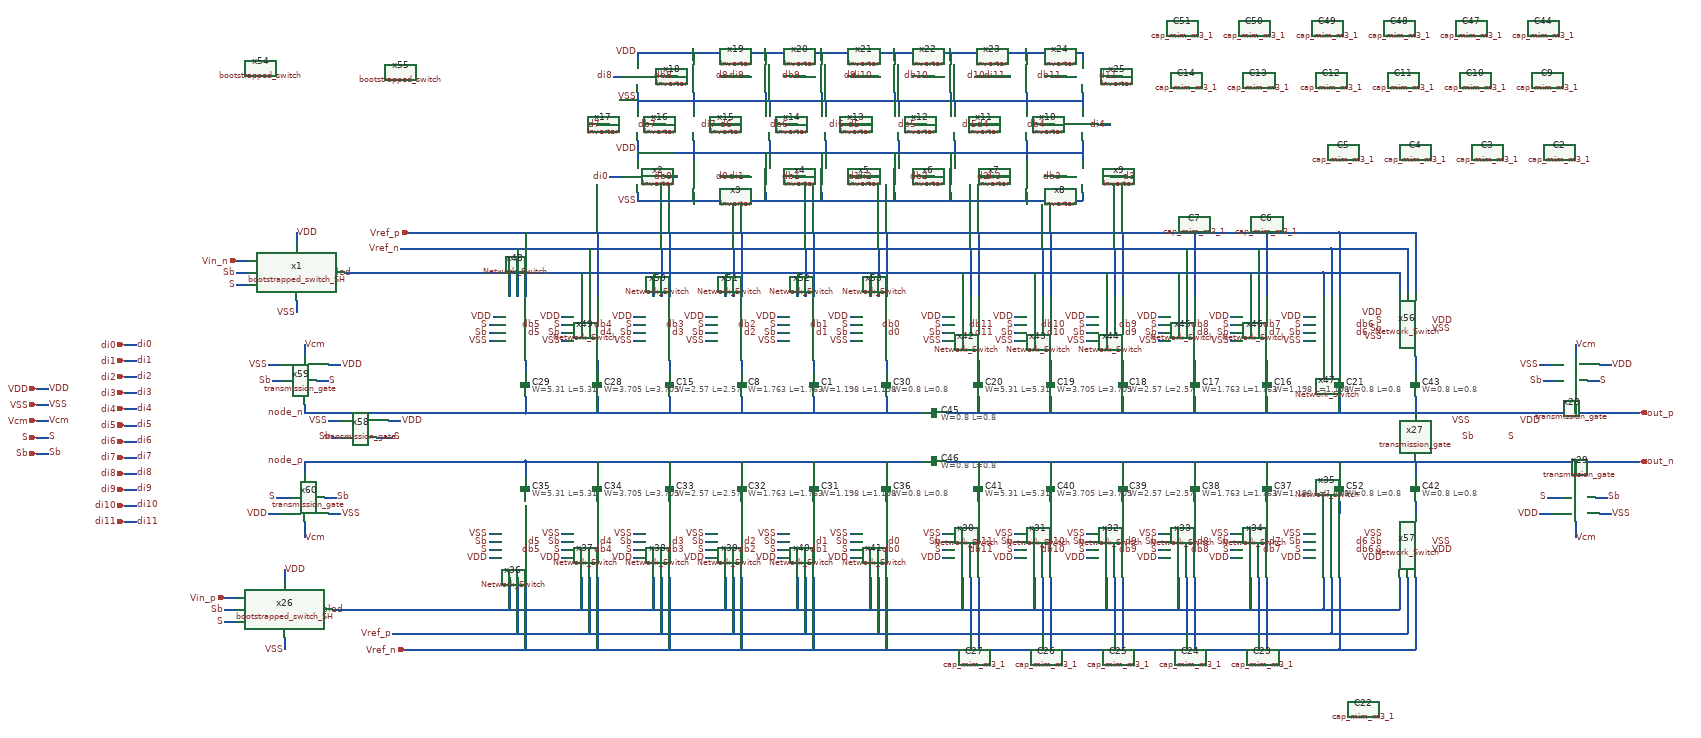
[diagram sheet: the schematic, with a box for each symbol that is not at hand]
v {xschem version=3.4.6 file_version=1.2}
G {}
K {}
V {}
S {}
E {}
N -790 70 -790 100 {lab=node_p}
N -530 70 190 70 {lab=node_p}
N 270 70 990 70 {lab=out_n}
N 1240 70 1240 100 {lab=out_n}
N 1060 70 1060 100 {lab=out_n}
N 880 70 880 100 {lab=out_n}
N 700 70 700 100 {lab=out_n}
N 520 70 520 100 {lab=out_n}
N 340 70 340 100 {lab=out_n}
N 110 70 110 100 {lab=node_p}
N -70 70 -70 100 {lab=node_p}
N -250 70 -250 100 {lab=node_p}
N -430 70 -430 100 {lab=node_p}
N -610 70 -610 100 {lab=node_p}
N -790 -80 -790 -50 {lab=node_n}
N -530 -50 190 -50 {lab=node_n}
N 270 -50 990 -50 {lab=out_p}
N 110 -80 110 -50 {lab=node_n}
N -70 -80 -70 -50 {lab=node_n}
N -250 -80 -250 -50 {lab=node_n}
N -430 -80 -430 -50 {lab=node_n}
N -610 -80 -610 -50 {lab=node_n}
N 1600 -50 1990 -50 {lab=out_p}
N 1600 70 1990 70 {lab=out_n}
N -660 70 -530 70 {lab=node_p}
N -790 70 -660 70 {lab=node_p}
N 990 70 1450 70 {lab=out_n}
N 110 180 110 200 {lab=#net1}
N -70 180 -70 200 {lab=#net2}
N -250 180 -250 200 {lab=#net3}
N -430 180 -430 200 {lab=#net4}
N -610 180 -610 200 {lab=#net5}
N -790 180 -790 200 {lab=#net6}
N 990 -50 1450 -50 {lab=out_p}
N 340 180 340 200 {lab=#net7}
N 520 180 520 200 {lab=#net8}
N 700 180 700 200 {lab=#net9}
N 880 180 880 200 {lab=#net10}
N 1240 180 1240 200 {lab=#net11}
N 1060 180 1060 200 {lab=#net12}
N -790 -50 -530 -50 {lab=node_n}
N 110 -180 110 -160 {lab=#net13}
N -70 -180 -70 -160 {lab=#net14}
N -250 -180 -250 -160 {lab=#net15}
N -430 -180 -430 -160 {lab=#net16}
N -610 -180 -610 -160 {lab=#net17}
N -790 -180 -790 -160 {lab=#net18}
N 1240 -180 1240 -160 {lab=#net19}
N 1060 -180 1060 -160 {lab=#net20}
N 880 -180 880 -160 {lab=#net21}
N 700 -180 700 -160 {lab=#net22}
N 520 -180 520 -160 {lab=#net23}
N 340 -180 340 -160 {lab=#net24}
N -830 -400 1200 -400 {lab=in_n_sampled}
N 70 -400 70 -340 {lab=in_n_sampled}
N -110 -400 -110 -340 {lab=in_n_sampled}
N -290 -400 -290 -340 {lab=in_n_sampled}
N -470 -400 -470 -340 {lab=in_n_sampled}
N -650 -400 -650 -340 {lab=in_n_sampled}
N -830 -400 -830 -340 {lab=in_n_sampled}
N -930 440 1200 440 {lab=in_p_sampled}
N 70 360 70 440 {lab=in_p_sampled}
N -110 360 -110 440 {lab=in_p_sampled}
N -470 360 -470 440 {lab=in_p_sampled}
N -650 360 -650 440 {lab=in_p_sampled}
N -830 360 -830 440 {lab=in_p_sampled}
N -2010 -70 -1980 -70 {lab=VSS}
N -2010 -110 -1980 -110 {lab=VDD}
N -2010 10 -1980 10 {lab=S}
N -2010 50 -1980 50 {lab=Sb}
N -1790 -100 -1760 -100 {lab=di3}
N -2010 -30 -1980 -30 {lab=Vcm}
N -1360 -500 -1360 -470 {lab=VDD}
N -1390 340 -1390 370 {lab=VDD}
N 250 -290 260 -290 {lab=VDD}
N 430 -290 440 -290 {lab=VDD}
N 610 -290 620 -290 {lab=VDD}
N 790 -290 800 -290 {lab=VDD}
N 970 -290 980 -290 {lab=VDD}
N 1150 -290 1160 -290 {lab=VDD}
N -870 -290 -860 -290 {lab=VDD}
N -700 -290 -690 -290 {lab=VDD}
N -520 -290 -510 -290 {lab=VDD}
N -340 -290 -330 -290 {lab=VDD}
N -160 -290 -150 -290 {lab=VDD}
N 20 -290 30 -290 {lab=VDD}
N 250 310 260 310 {lab=VDD}
N 430 310 440 310 {lab=VDD}
N 610 310 620 310 {lab=VDD}
N 790 310 800 310 {lab=VDD}
N 970 310 980 310 {lab=VDD}
N 1150 310 1160 310 {lab=VDD}
N -880 310 -870 310 {lab=VDD}
N -700 310 -690 310 {lab=VDD}
N -520 310 -510 310 {lab=VDD}
N -160 310 -150 310 {lab=VDD}
N -340 310 -330 310 {lab=VDD}
N 20 310 30 310 {lab=VDD}
N -1360 -330 -1360 -300 {lab=VSS}
N -1390 510 -1390 540 {lab=VSS}
N 250 250 260 250 {lab=VSS}
N 430 250 440 250 {lab=VSS}
N 610 250 620 250 {lab=VSS}
N 790 250 800 250 {lab=VSS}
N 970 250 980 250 {lab=VSS}
N 1150 250 1160 250 {lab=VSS}
N -880 250 -870 250 {lab=VSS}
N -700 250 -690 250 {lab=VSS}
N -520 250 -510 250 {lab=VSS}
N -340 250 -330 250 {lab=VSS}
N -160 250 -150 250 {lab=VSS}
N 20 250 30 250 {lab=VSS}
N 250 -230 260 -230 {lab=VSS}
N 430 -230 440 -230 {lab=VSS}
N 610 -230 620 -230 {lab=VSS}
N 790 -230 800 -230 {lab=VSS}
N 970 -230 980 -230 {lab=VSS}
N 1150 -230 1160 -230 {lab=VSS}
N -880 -230 -870 -230 {lab=VSS}
N -700 -230 -690 -230 {lab=VSS}
N -520 -230 -510 -230 {lab=VSS}
N -340 -230 -330 -230 {lab=VSS}
N -160 -230 -150 -230 {lab=VSS}
N 20 -230 30 -230 {lab=VSS}
N -1030 440 -930 440 {lab=in_p_sampled}
N -910 -460 1220 -460 {lab=Vref_n}
N 90 -460 90 -340 {lab=Vref_n}
N 110 -500 110 -340 {lab=Vref_p}
N -930 -500 1240 -500 {lab=Vref_p}
N 320 -460 320 -340 {lab=Vref_n}
N 340 -500 340 -340 {lab=Vref_p}
N 500 -460 500 -340 {lab=Vref_n}
N 520 -500 520 -340 {lab=Vref_p}
N 680 -460 680 -340 {lab=Vref_n}
N 700 -500 700 -340 {lab=Vref_p}
N 860 -460 860 -340 {lab=Vref_n}
N 880 -500 880 -340 {lab=Vref_p}
N 1040 -460 1040 -340 {lab=Vref_n}
N 1060 -500 1060 -340 {lab=Vref_p}
N 1220 -460 1220 -340 {lab=Vref_n}
N 1240 -500 1240 -340 {lab=Vref_p}
N -810 -460 -810 -340 {lab=Vref_n}
N -790 -500 -790 -340 {lab=Vref_p}
N -630 -460 -630 -340 {lab=Vref_n}
N -610 -500 -610 -340 {lab=Vref_p}
N -450 -460 -450 -340 {lab=Vref_n}
N -430 -500 -430 -340 {lab=Vref_p}
N -270 -460 -270 -340 {lab=Vref_n}
N -250 -500 -250 -340 {lab=Vref_p}
N -90 -460 -90 -340 {lab=Vref_n}
N -70 -500 -70 -340 {lab=Vref_p}
N 90 360 90 500 {lab=Vref_p}
N -910 500 1220 500 {lab=Vref_p}
N 110 360 110 540 {lab=Vref_n}
N -930 540 1240 540 {lab=Vref_n}
N 320 360 320 500 {lab=Vref_p}
N 340 360 340 540 {lab=Vref_n}
N 500 360 500 500 {lab=Vref_p}
N 520 360 520 540 {lab=Vref_n}
N 680 360 680 500 {lab=Vref_p}
N 700 360 700 540 {lab=Vref_n}
N 860 360 860 500 {lab=Vref_p}
N 880 360 880 540 {lab=Vref_n}
N 1040 360 1040 500 {lab=Vref_p}
N 1060 360 1060 540 {lab=Vref_n}
N 1220 360 1220 500 {lab=Vref_p}
N 1240 360 1240 540 {lab=Vref_n}
N -810 360 -810 500 {lab=Vref_p}
N -790 360 -790 540 {lab=Vref_n}
N -630 360 -630 500 {lab=Vref_p}
N -610 360 -610 540 {lab=Vref_n}
N -450 360 -450 500 {lab=Vref_p}
N -430 360 -430 540 {lab=Vref_n}
N -270 360 -270 500 {lab=Vref_p}
N -250 360 -250 540 {lab=Vref_n}
N -90 360 -90 500 {lab=Vref_p}
N -70 360 -70 540 {lab=Vref_n}
N -1790 -220 -1760 -220 {lab=di0}
N -1790 -180 -1760 -180 {lab=di1}
N -1790 -140 -1760 -140 {lab=di2}
N -1790 -20 -1760 -20 {lab=di5}
N -1790 -60 -1760 -60 {lab=di4}
N -1790 60 -1760 60 {lab=di7}
N -1790 20 -1760 20 {lab=di6}
N -1790 140 -1760 140 {lab=di9}
N -1790 100 -1760 100 {lab=di8}
N -1790 220 -1760 220 {lab=di11}
N -1790 180 -1760 180 {lab=di10}
N 250 -270 260 -270 {lab=S}
N 250 -250 260 -250 {lab=Sb}
N 430 -270 440 -270 {lab=S}
N 430 -250 440 -250 {lab=Sb}
N 610 -270 620 -270 {lab=S}
N 610 -250 620 -250 {lab=Sb}
N 790 -270 800 -270 {lab=S}
N 790 -250 800 -250 {lab=Sb}
N 970 -270 980 -270 {lab=S}
N 970 -250 980 -250 {lab=Sb}
N 1150 -270 1160 -270 {lab=S}
N 1150 -250 1160 -250 {lab=Sb}
N -880 -270 -870 -270 {lab=S}
N -880 -250 -870 -250 {lab=Sb}
N -700 -270 -690 -270 {lab=S}
N -700 -250 -690 -250 {lab=Sb}
N -520 -270 -510 -270 {lab=S}
N -520 -250 -510 -250 {lab=Sb}
N -340 -270 -330 -270 {lab=S}
N -340 -250 -330 -250 {lab=Sb}
N -160 -270 -150 -270 {lab=S}
N -160 -250 -150 -250 {lab=Sb}
N 20 -270 30 -270 {lab=S}
N 20 -250 30 -250 {lab=Sb}
N 250 290 260 290 {lab=S}
N 250 270 260 270 {lab=Sb}
N 430 290 440 290 {lab=S}
N 430 270 440 270 {lab=Sb}
N 610 290 620 290 {lab=S}
N 610 270 620 270 {lab=Sb}
N 790 290 800 290 {lab=S}
N 790 270 800 270 {lab=Sb}
N 970 290 980 290 {lab=S}
N 970 270 980 270 {lab=Sb}
N 1150 290 1160 290 {lab=S}
N 1150 270 1160 270 {lab=Sb}
N -880 290 -870 290 {lab=S}
N -880 270 -870 270 {lab=Sb}
N -700 290 -690 290 {lab=S}
N -700 270 -690 270 {lab=Sb}
N -520 290 -510 290 {lab=S}
N -520 270 -510 270 {lab=Sb}
N -340 290 -330 290 {lab=S}
N -340 270 -330 270 {lab=Sb}
N -160 290 -150 290 {lab=S}
N -160 270 -150 270 {lab=Sb}
N 20 290 30 290 {lab=S}
N 20 270 30 270 {lab=Sb}
N -1510 -430 -1480 -430 {lab=Vin_n}
N -1540 410 -1510 410 {lab=Vin_p}
N -1510 -370 -1480 -370 {lab=S}
N -1510 -400 -1480 -400 {lab=Sb}
N -1540 470 -1510 470 {lab=S}
N -1540 440 -1510 440 {lab=Sb}
N 1450 70 1600 70 {lab=out_n}
N 1450 -50 1600 -50 {lab=out_p}
N 340 -160 340 -150 {lab=#net24}
N -790 -90 -790 -80 {lab=node_n}
N 520 -160 520 -150 {lab=#net23}
N -610 -90 -610 -80 {lab=node_n}
N -430 -90 -430 -80 {lab=node_n}
N 700 -160 700 -150 {lab=#net22}
N 880 -160 880 -150 {lab=#net21}
N -250 -90 -250 -80 {lab=node_n}
N -70 -90 -70 -80 {lab=node_n}
N 1060 -160 1060 -150 {lab=#net20}
N 1240 -160 1240 -150 {lab=#net19}
N 110 -90 110 -80 {lab=node_n}
N 190 -50 200 -50 {lab=node_n}
N 260 -50 270 -50 {lab=out_p}
N -790 -160 -790 -150 {lab=#net18}
N -610 -160 -610 -150 {lab=#net17}
N -430 -160 -430 -150 {lab=#net16}
N -250 -160 -250 -150 {lab=#net15}
N -70 -160 -70 -150 {lab=#net14}
N 110 -160 110 -150 {lab=#net13}
N 1240 100 1240 110 {lab=out_n}
N 1060 100 1060 110 {lab=out_n}
N 880 100 880 110 {lab=out_n}
N 700 100 700 110 {lab=out_n}
N 520 100 520 110 {lab=out_n}
N 340 100 340 110 {lab=out_n}
N 260 70 270 70 {lab=out_n}
N 190 70 200 70 {lab=node_p}
N -790 100 -790 110 {lab=node_p}
N 340 170 340 180 {lab=#net7}
N 520 170 520 180 {lab=#net8}
N -610 100 -610 110 {lab=node_p}
N -430 100 -430 110 {lab=node_p}
N 700 170 700 180 {lab=#net9}
N 880 170 880 180 {lab=#net10}
N -250 100 -250 110 {lab=node_p}
N 110 100 110 110 {lab=node_p}
N -70 100 -70 110 {lab=node_p}
N 1060 170 1060 180 {lab=#net12}
N 1240 170 1240 180 {lab=#net11}
N -1010 -50 -790 -50 {lab=node_n}
N -1010 -500 -930 -500 {lab=Vref_p}
N -1080 -500 -1010 -500 {lab=Vref_p}
N -1010 70 -790 70 {lab=node_p}
N -1270 440 -1030 440 {lab=in_p_sampled}
N -1010 540 -930 540 {lab=Vref_n}
N -1090 540 -1010 540 {lab=Vref_n}
N -1240 -400 -830 -400 {lab=in_n_sampled}
N -510 -730 -510 -680 {lab=VDD}
N -510 -700 600 -700 {lab=VDD}
N 600 -700 600 -680 {lab=VDD}
N 600 -720 600 -700 {lab=VDD}
N 600 -730 600 -720 {lab=VDD}
N 460 -730 460 -700 {lab=VDD}
N 460 -700 460 -690 {lab=VDD}
N 460 -690 460 -680 {lab=VDD}
N 270 -700 270 -680 {lab=VDD}
N 280 -730 280 -700 {lab=VDD}
N 130 -700 130 -680 {lab=VDD}
N -50 -700 -50 -680 {lab=VDD}
N -190 -700 -190 -680 {lab=VDD}
N 140 -730 140 -700 {lab=VDD}
N -40 -730 -40 -700 {lab=VDD}
N -180 -730 -180 -700 {lab=VDD}
N -370 -730 -370 -700 {lab=VDD}
N -370 -700 -370 -680 {lab=VDD}
N -510 -850 -510 -810 {lab=VSS}
N -510 -830 600 -830 {lab=VSS}
N 600 -830 600 -810 {lab=VSS}
N 600 -850 600 -830 {lab=VSS}
N 460 -850 460 -830 {lab=VSS}
N 460 -830 460 -810 {lab=VSS}
N 280 -830 280 -810 {lab=VSS}
N 270 -850 270 -830 {lab=VSS}
N 140 -830 140 -810 {lab=VSS}
N 130 -850 130 -830 {lab=VSS}
N -50 -850 -50 -830 {lab=VSS}
N -40 -830 -40 -810 {lab=VSS}
N -180 -830 -180 -810 {lab=VSS}
N -190 -850 -190 -830 {lab=VSS}
N -370 -850 -370 -830 {lab=VSS}
N -370 -830 -370 -810 {lab=VSS}
N -510 -950 -510 -930 {lab=VDD}
N -510 -950 600 -950 {lab=VDD}
N 600 -950 600 -930 {lab=VDD}
N 460 -950 460 -930 {lab=VDD}
N 270 -950 270 -930 {lab=VDD}
N 130 -950 130 -930 {lab=VDD}
N -370 -950 -370 -930 {lab=VDD}
N -190 -950 -190 -930 {lab=VDD}
N -50 -950 -50 -930 {lab=VDD}
N -440 -640 -410 -640 {lab=db0}
N -290 -640 -280 -640 {lab=d0}
N -300 -640 -290 -640 {lab=d0}
N -250 -640 -230 -640 {lab=di1}
N -110 -640 -90 -640 {lab=db1}
N -120 -640 -110 -640 {lab=db1}
N -580 -640 -550 -640 {lab=di0}
N -470 -770 -440 -770 {lab=db7}
N -330 -770 -300 -770 {lab=di7}
N -610 -770 -590 -770 {lab=d7}
N -280 -770 -260 -770 {lab=d6}
N -260 -770 -250 -770 {lab=d6}
N -140 -770 -110 -770 {lab=db6}
N 0 -770 20 -770 {lab=di6}
N 50 -770 70 -770 {lab=d5}
N 20 -640 50 -640 {lab=d1}
N 70 -640 90 -640 {lab=di2}
N 200 -640 230 -640 {lab=db2}
N 340 -640 370 -640 {lab=d2}
N 400 -640 420 -640 {lab=di3}
N 180 -770 200 -770 {lab=db5}
N 320 -770 340 -770 {lab=di5}
N 360 -770 380 -770 {lab=d4}
N 500 -770 530 -770 {lab=db4}
N 640 -770 670 -770 {lab=di4}
N 680 -640 710 -640 {lab=d3}
N 670 -640 680 -640 {lab=d3}
N 530 -640 560 -640 {lab=db3}
N 600 -600 600 -580 {lab=VSS}
N -510 -580 600 -580 {lab=VSS}
N -510 -600 -510 -580 {lab=VSS}
N -370 -600 -370 -580 {lab=VSS}
N -190 -600 -190 -580 {lab=VSS}
N -50 -600 -50 -580 {lab=VSS}
N 460 -600 460 -580 {lab=VSS}
N 270 -600 270 -580 {lab=VSS}
N 130 -600 130 -580 {lab=VSS}
N 680 -890 700 -890 {lab=d11}
N 670 -890 680 -890 {lab=d11}
N 530 -890 560 -890 {lab=db11}
N 400 -890 420 -890 {lab=di11}
N 200 -890 230 -890 {lab=db10}
N 340 -890 370 -890 {lab=d10}
N 70 -890 90 -890 {lab=di10}
N 20 -890 50 -890 {lab=d9}
N -440 -890 -410 -890 {lab=db8}
N -300 -890 -270 -890 {lab=d8}
N -250 -890 -230 -890 {lab=di9}
N -120 -890 -90 -890 {lab=db9}
N -570 -890 -550 -890 {lab=di8}
N -590 -770 -580 -770 {lab=d7}
N 380 -770 390 -770 {lab=d4}
N 200 -770 210 -770 {lab=db5}
N 300 -360 300 -340 {lab=in_n_sampled}
N 480 -360 480 -340 {lab=in_n_sampled}
N 660 -360 660 -340 {lab=in_n_sampled}
N 840 -360 840 -340 {lab=in_n_sampled}
N 1020 -370 1020 -340 {lab=in_n_sampled}
N 1200 -360 1200 -340 {lab=in_n_sampled}
N 300 360 300 390 {lab=in_p_sampled}
N 480 360 480 390 {lab=in_p_sampled}
N 660 360 660 390 {lab=in_p_sampled}
N 840 360 840 390 {lab=in_p_sampled}
N 1020 360 1020 390 {lab=in_p_sampled}
N 1200 360 1200 390 {lab=in_p_sampled}
N 300 -400 300 -360 {lab=in_n_sampled}
N 480 -400 480 -360 {lab=in_n_sampled}
N 660 -400 660 -360 {lab=in_n_sampled}
N 840 -400 840 -360 {lab=in_n_sampled}
N 1200 -400 1200 -360 {lab=in_n_sampled}
N 1020 -400 1020 -370 {lab=in_n_sampled}
N 300 390 300 440 {lab=in_p_sampled}
N 480 390 480 440 {lab=in_p_sampled}
N 660 390 660 440 {lab=in_p_sampled}
N 840 390 840 430 {lab=in_p_sampled}
N 1020 390 1020 440 {lab=in_p_sampled}
N 1200 390 1200 440 {lab=in_p_sampled}
N 1830 -220 1830 -190 {lab=Vcm}
N 1830 -70 1830 -50 {lab=out_p}
N 1830 70 1830 100 {lab=out_n}
N 1860 -130 1890 -130 {lab=S}
N 1750 -130 1780 -130 {lab=Sb}
N 1740 -170 1770 -170 {lab=VSS}
N 1890 -170 1920 -170 {lab=VDD}
N 1880 160 1910 160 {lab=Sb}
N 1760 160 1800 160 {lab=S}
N 1830 220 1830 240 {lab=Vcm}
N 1890 200 1920 200 {lab=VSS}
N 1740 200 1770 200 {lab=VDD}
N 1830 240 1830 260 {lab=Vcm}
N 330 -890 340 -890 {lab=d10}
N -1030 -460 -910 -460 {lab=Vref_n}
N 1410 -460 1410 -350 {lab=Vref_n}
N -1100 -460 -1030 -460 {lab=Vref_n}
N 1430 -500 1430 -350 {lab=Vref_p}
N 1390 -400 1390 -350 {lab=in_n_sampled}
N -1050 -50 -1010 -50 {lab=node_n}
N -1050 70 -1010 70 {lab=node_p}
N -1120 500 -910 500 {lab=Vref_p}
N 1410 360 1410 500 {lab=Vref_p}
N 1430 360 1430 540 {lab=Vref_n}
N 1390 360 1390 440 {lab=in_p_sampled}
N 340 -90 340 -50 {lab=out_p}
N 520 -90 520 -50 {lab=out_p}
N 700 -90 700 -50 {lab=out_p}
N 880 -90 880 -50 {lab=out_p}
N 1060 -90 1060 -50 {lab=out_p}
N 1240 -90 1240 -50 {lab=out_p}
N 1200 -400 1390 -400 {lab=in_n_sampled}
N 1220 -460 1410 -460 {lab=Vref_n}
N 1240 -500 1430 -500 {lab=Vref_p}
N 1200 440 1390 440 {lab=in_p_sampled}
N 1220 500 1410 500 {lab=Vref_p}
N 1240 540 1430 540 {lab=Vref_n}
N 1430 -90 1430 -50 {lab=out_p}
N 1430 70 1430 110 {lab=out_n}
N -290 360 -290 440 {lab=in_p_sampled}
N 840 430 840 440 {lab=in_p_sampled}
N 1430 170 1430 200 {lab=#net25}
N 1430 -190 1430 -150 {lab=#net26}
N -1340 -220 -1340 -190 {lab=Vcm}
N -1340 -70 -1340 -50 {lab=node_n}
N -1340 70 -1340 100 {lab=node_p}
N -1310 -130 -1280 -130 {lab=S}
N -1420 -130 -1390 -130 {lab=Sb}
N -1430 -170 -1400 -170 {lab=VSS}
N -1280 -170 -1250 -170 {lab=VDD}
N -1290 160 -1260 160 {lab=Sb}
N -1410 160 -1370 160 {lab=S}
N -1340 220 -1340 240 {lab=Vcm}
N -1280 200 -1250 200 {lab=VSS}
N -1430 200 -1400 200 {lab=VDD}
N -1340 240 -1340 260 {lab=Vcm}
N -1340 -50 -1190 -50 {lab=node_n}
N -1190 -50 -1050 -50 {lab=node_n}
N -1340 70 -1190 70 {lab=node_p}
N -1190 70 -1050 70 {lab=node_p}
N -1280 -30 -1250 -30 {lab=VSS}
N -1130 -30 -1100 -30 {lab=VDD}
N -1160 10 -1120 10 {lab=S}
N -1270 10 -1240 10 {lab=Sb}
N -430 -90 -430 -50 {lab=node_n}
N -250 -90 -250 -50 {lab=node_n}
N -70 -90 -70 -50 {lab=node_n}
N 110 -90 110 -50 {lab=node_n}
N -430 170 -430 210 {lab=#net4}
N -250 170 -250 210 {lab=#net3}
N -70 170 -70 210 {lab=#net2}
N 110 170 110 210 {lab=#net1}
C {Network_Switch.sym} 320 280 2 1 {name=x30}
C {Network_Switch.sym} 500 280 2 1 {name=x31}
C {Network_Switch.sym} 680 280 2 1 {name=x32}
C {Network_Switch.sym} 860 280 2 1 {name=x33}
C {Network_Switch.sym} 1040 280 2 1 {name=x34}
C {Network_Switch.sym} 1220 280 2 1 {name=x35}
C {Network_Switch.sym} -810 280 2 1 {name=x36}
C {Network_Switch.sym} -630 280 2 1 {name=x37}
C {Network_Switch.sym} -450 280 2 1 {name=x38}
C {Network_Switch.sym} -270 280 2 1 {name=x39}
C {Network_Switch.sym} -90 280 2 1 {name=x40}
C {Network_Switch.sym} 90 280 2 1 {name=x41}
C {Network_Switch.sym} 320 -260 0 0 {name=x42}
C {Network_Switch.sym} 500 -260 0 0 {name=x43}
C {Network_Switch.sym} 680 -260 0 0 {name=x44}
C {Network_Switch.sym} 860 -260 0 0 {name=x45}
C {Network_Switch.sym} 1040 -260 0 0 {name=x46}
C {Network_Switch.sym} 1220 -260 0 0 {name=x47}
C {Network_Switch.sym} -810 -260 0 0 {name=x48}
C {Network_Switch.sym} -630 -260 0 0 {name=x49}
C {Network_Switch.sym} -450 -260 0 0 {name=x50}
C {Network_Switch.sym} -270 -260 0 0 {name=x51}
C {Network_Switch.sym} -90 -260 0 0 {name=x52}
C {Network_Switch.sym} 90 -260 0 0 {name=x53}
C {bootstrapped_switch.sym} -1450 -910 0 0 {name=x54
spice_ignore=true}
C {bootstrapped_switch.sym} -1100 -900 0 0 {name=x55
spice_ignore=true}
C {devices/ipin.sym} -2010 -110 0 0 {name=p5 lab=VDD}
C {devices/ipin.sym} -2010 -70 0 0 {name=p6 lab=VSS}
C {devices/ipin.sym} -2010 10 0 0 {name=p7 lab=S}
C {devices/lab_pin.sym} -1980 -110 2 0 {name=p8 sig_type=std_logic lab=VDD}
C {devices/lab_pin.sym} -1980 -70 2 0 {name=p9 sig_type=std_logic lab=VSS}
C {devices/ipin.sym} -2010 50 0 0 {name=p18 lab=Sb}
C {devices/ipin.sym} -1790 -100 0 0 {name=p19 lab=di3}
C {devices/lab_pin.sym} -1980 10 2 0 {name=p21 sig_type=std_logic lab=S}
C {devices/lab_pin.sym} -1980 50 2 0 {name=p22 sig_type=std_logic lab=Sb}
C {devices/lab_pin.sym} -1760 -100 2 0 {name=p27 sig_type=std_logic lab=di3}
C {devices/ipin.sym} -2010 -30 0 0 {name=p1 lab=Vcm}
C {devices/lab_pin.sym} -1980 -30 2 0 {name=p2 sig_type=std_logic lab=Vcm}
C {devices/lab_pin.sym} -1360 -500 2 0 {name=p3 sig_type=std_logic lab=VDD}
C {devices/lab_pin.sym} -1390 340 2 0 {name=p4 sig_type=std_logic lab=VDD}
C {devices/lab_pin.sym} 250 -290 0 0 {name=p10 sig_type=std_logic lab=VDD}
C {devices/lab_pin.sym} 430 -290 0 0 {name=p11 sig_type=std_logic lab=VDD}
C {devices/lab_pin.sym} 610 -290 0 0 {name=p12 sig_type=std_logic lab=VDD}
C {devices/lab_pin.sym} 790 -290 0 0 {name=p13 sig_type=std_logic lab=VDD}
C {devices/lab_pin.sym} 970 -290 0 0 {name=p14 sig_type=std_logic lab=VDD}
C {devices/lab_pin.sym} 1150 -290 0 0 {name=p15 sig_type=std_logic lab=VDD}
C {devices/lab_pin.sym} -870 -290 0 0 {name=p16 sig_type=std_logic lab=VDD}
C {devices/lab_pin.sym} -700 -290 0 0 {name=p17 sig_type=std_logic lab=VDD}
C {devices/lab_pin.sym} -520 -290 0 0 {name=p23 sig_type=std_logic lab=VDD}
C {devices/lab_pin.sym} -340 -290 0 0 {name=p24 sig_type=std_logic lab=VDD}
C {devices/lab_pin.sym} -160 -290 0 0 {name=p25 sig_type=std_logic lab=VDD}
C {devices/lab_pin.sym} 20 -290 0 0 {name=p26 sig_type=std_logic lab=VDD}
C {devices/lab_pin.sym} 250 310 0 0 {name=p29 sig_type=std_logic lab=VDD}
C {devices/lab_pin.sym} 430 310 0 0 {name=p30 sig_type=std_logic lab=VDD}
C {devices/lab_pin.sym} 610 310 0 0 {name=p31 sig_type=std_logic lab=VDD}
C {devices/lab_pin.sym} 790 310 0 0 {name=p32 sig_type=std_logic lab=VDD}
C {devices/lab_pin.sym} 970 310 0 0 {name=p33 sig_type=std_logic lab=VDD}
C {devices/lab_pin.sym} 1150 310 0 0 {name=p34 sig_type=std_logic lab=VDD}
C {devices/lab_pin.sym} -880 310 0 0 {name=p35 sig_type=std_logic lab=VDD}
C {devices/lab_pin.sym} -700 310 0 0 {name=p36 sig_type=std_logic lab=VDD}
C {devices/lab_pin.sym} -520 310 0 0 {name=p37 sig_type=std_logic lab=VDD}
C {devices/lab_pin.sym} -160 310 0 0 {name=p38 sig_type=std_logic lab=VDD}
C {devices/lab_pin.sym} -340 310 0 0 {name=p39 sig_type=std_logic lab=VDD}
C {devices/lab_pin.sym} 20 310 0 0 {name=p40 sig_type=std_logic lab=VDD}
C {devices/lab_pin.sym} -1360 -300 0 0 {name=p44 sig_type=std_logic lab=VSS}
C {devices/lab_pin.sym} -1390 540 0 0 {name=p45 sig_type=std_logic lab=VSS}
C {devices/lab_pin.sym} 250 250 0 0 {name=p46 sig_type=std_logic lab=VSS}
C {devices/lab_pin.sym} 430 250 0 0 {name=p47 sig_type=std_logic lab=VSS}
C {devices/lab_pin.sym} 610 250 0 0 {name=p48 sig_type=std_logic lab=VSS}
C {devices/lab_pin.sym} 790 250 0 0 {name=p49 sig_type=std_logic lab=VSS}
C {devices/lab_pin.sym} 970 250 0 0 {name=p50 sig_type=std_logic lab=VSS}
C {devices/lab_pin.sym} 1150 250 0 0 {name=p51 sig_type=std_logic lab=VSS}
C {devices/lab_pin.sym} -880 250 0 0 {name=p52 sig_type=std_logic lab=VSS}
C {devices/lab_pin.sym} -700 250 0 0 {name=p53 sig_type=std_logic lab=VSS}
C {devices/lab_pin.sym} -520 250 0 0 {name=p54 sig_type=std_logic lab=VSS}
C {devices/lab_pin.sym} -340 250 0 0 {name=p55 sig_type=std_logic lab=VSS}
C {devices/lab_pin.sym} -160 250 0 0 {name=p56 sig_type=std_logic lab=VSS}
C {devices/lab_pin.sym} 20 250 0 0 {name=p57 sig_type=std_logic lab=VSS}
C {devices/lab_pin.sym} 250 -230 0 0 {name=p58 sig_type=std_logic lab=VSS}
C {devices/lab_pin.sym} 430 -230 0 0 {name=p59 sig_type=std_logic lab=VSS}
C {devices/lab_pin.sym} 610 -230 0 0 {name=p60 sig_type=std_logic lab=VSS}
C {devices/lab_pin.sym} 790 -230 0 0 {name=p61 sig_type=std_logic lab=VSS}
C {devices/lab_pin.sym} 970 -230 0 0 {name=p62 sig_type=std_logic lab=VSS}
C {devices/lab_pin.sym} 1150 -230 0 0 {name=p63 sig_type=std_logic lab=VSS}
C {devices/lab_pin.sym} -880 -230 0 0 {name=p64 sig_type=std_logic lab=VSS}
C {devices/lab_pin.sym} -700 -230 0 0 {name=p65 sig_type=std_logic lab=VSS}
C {devices/lab_pin.sym} -520 -230 0 0 {name=p66 sig_type=std_logic lab=VSS}
C {devices/lab_pin.sym} -340 -230 0 0 {name=p67 sig_type=std_logic lab=VSS}
C {devices/lab_pin.sym} -160 -230 0 0 {name=p68 sig_type=std_logic lab=VSS}
C {devices/lab_pin.sym} 20 -230 0 0 {name=p69 sig_type=std_logic lab=VSS}
C {devices/opin.sym} 1990 -50 0 0 {name=p76 lab=out_p}
C {devices/opin.sym} 1990 70 0 0 {name=p77 lab=out_n
}
C {devices/ipin.sym} -1080 -500 0 0 {name=p78 lab=Vref_p}
C {devices/ipin.sym} -1090 540 0 0 {name=p79 lab=Vref_n}
C {devices/lab_pin.sym} -1120 500 0 0 {name=p80 sig_type=std_logic lab=Vref_p}
C {devices/lab_pin.sym} -1100 -460 0 0 {name=p81 sig_type=std_logic lab=Vref_n}
C {devices/ipin.sym} -1790 -220 0 0 {name=p82 lab=di0}
C {devices/lab_pin.sym} -1760 -220 2 0 {name=p84 sig_type=std_logic lab=di0}
C {devices/ipin.sym} -1790 -180 0 0 {name=p86 lab=di1}
C {devices/lab_pin.sym} -1760 -180 2 0 {name=p88 sig_type=std_logic lab=di1}
C {devices/ipin.sym} -1790 -140 0 0 {name=p90 lab=di2}
C {devices/lab_pin.sym} -1760 -140 2 0 {name=p92 sig_type=std_logic lab=di2}
C {devices/ipin.sym} -1790 -20 0 0 {name=p94 lab=di5}
C {devices/lab_pin.sym} -1760 -20 2 0 {name=p96 sig_type=std_logic lab=di5}
C {devices/ipin.sym} -1790 -60 0 0 {name=p98 lab=di4}
C {devices/lab_pin.sym} -1760 -60 2 0 {name=p100 sig_type=std_logic lab=di4}
C {devices/ipin.sym} -1790 60 0 0 {name=p102 lab=di7}
C {devices/lab_pin.sym} -1760 60 2 0 {name=p104 sig_type=std_logic lab=di7}
C {devices/ipin.sym} -1790 20 0 0 {name=p106 lab=di6}
C {devices/lab_pin.sym} -1760 20 2 0 {name=p108 sig_type=std_logic lab=di6}
C {devices/ipin.sym} -1790 140 0 0 {name=p110 lab=di9}
C {devices/lab_pin.sym} -1760 140 2 0 {name=p112 sig_type=std_logic lab=di9}
C {devices/ipin.sym} -1790 100 0 0 {name=p114 lab=di8}
C {devices/lab_pin.sym} -1760 100 2 0 {name=p116 sig_type=std_logic lab=di8}
C {devices/ipin.sym} -1790 220 0 0 {name=p118 lab=di11}
C {devices/lab_pin.sym} -1760 220 2 0 {name=p120 sig_type=std_logic lab=di11}
C {devices/ipin.sym} -1790 180 0 0 {name=p122 lab=di10}
C {devices/lab_pin.sym} -1760 180 2 0 {name=p124 sig_type=std_logic lab=di10}
C {devices/lab_pin.sym} 250 -270 2 1 {name=p126 sig_type=std_logic lab=S}
C {devices/lab_pin.sym} 250 -250 2 1 {name=p127 sig_type=std_logic lab=Sb}
C {devices/lab_pin.sym} 430 -270 2 1 {name=p128 sig_type=std_logic lab=S}
C {devices/lab_pin.sym} 430 -250 2 1 {name=p129 sig_type=std_logic lab=Sb}
C {devices/lab_pin.sym} 610 -270 2 1 {name=p130 sig_type=std_logic lab=S}
C {devices/lab_pin.sym} 610 -250 2 1 {name=p131 sig_type=std_logic lab=Sb}
C {devices/lab_pin.sym} 790 -270 2 1 {name=p132 sig_type=std_logic lab=S}
C {devices/lab_pin.sym} 790 -250 2 1 {name=p133 sig_type=std_logic lab=Sb}
C {devices/lab_pin.sym} 970 -270 2 1 {name=p134 sig_type=std_logic lab=S}
C {devices/lab_pin.sym} 970 -250 2 1 {name=p135 sig_type=std_logic lab=Sb}
C {devices/lab_pin.sym} 1150 -270 2 1 {name=p136 sig_type=std_logic lab=S}
C {devices/lab_pin.sym} 1150 -250 2 1 {name=p137 sig_type=std_logic lab=Sb}
C {devices/lab_pin.sym} -880 -270 2 1 {name=p138 sig_type=std_logic lab=S}
C {devices/lab_pin.sym} -880 -250 2 1 {name=p139 sig_type=std_logic lab=Sb}
C {devices/lab_pin.sym} -700 -270 2 1 {name=p140 sig_type=std_logic lab=S}
C {devices/lab_pin.sym} -700 -250 2 1 {name=p141 sig_type=std_logic lab=Sb}
C {devices/lab_pin.sym} -520 -270 2 1 {name=p142 sig_type=std_logic lab=S}
C {devices/lab_pin.sym} -520 -250 2 1 {name=p143 sig_type=std_logic lab=Sb}
C {devices/lab_pin.sym} -340 -270 2 1 {name=p144 sig_type=std_logic lab=S}
C {devices/lab_pin.sym} -340 -250 2 1 {name=p145 sig_type=std_logic lab=Sb}
C {devices/lab_pin.sym} -160 -270 2 1 {name=p146 sig_type=std_logic lab=S}
C {devices/lab_pin.sym} -160 -250 2 1 {name=p147 sig_type=std_logic lab=Sb}
C {devices/lab_pin.sym} 20 -270 2 1 {name=p148 sig_type=std_logic lab=S}
C {devices/lab_pin.sym} 20 -250 2 1 {name=p149 sig_type=std_logic lab=Sb}
C {devices/lab_pin.sym} 250 290 2 1 {name=p152 sig_type=std_logic lab=S}
C {devices/lab_pin.sym} 250 270 2 1 {name=p153 sig_type=std_logic lab=Sb}
C {devices/lab_pin.sym} 430 290 2 1 {name=p150 sig_type=std_logic lab=S}
C {devices/lab_pin.sym} 430 270 2 1 {name=p151 sig_type=std_logic lab=Sb}
C {devices/lab_pin.sym} 610 290 2 1 {name=p154 sig_type=std_logic lab=S}
C {devices/lab_pin.sym} 610 270 2 1 {name=p155 sig_type=std_logic lab=Sb}
C {devices/lab_pin.sym} 790 290 2 1 {name=p156 sig_type=std_logic lab=S}
C {devices/lab_pin.sym} 790 270 2 1 {name=p157 sig_type=std_logic lab=Sb}
C {devices/lab_pin.sym} 970 290 2 1 {name=p158 sig_type=std_logic lab=S}
C {devices/lab_pin.sym} 970 270 2 1 {name=p159 sig_type=std_logic lab=Sb}
C {devices/lab_pin.sym} 1150 290 2 1 {name=p160 sig_type=std_logic lab=S}
C {devices/lab_pin.sym} 1150 270 2 1 {name=p161 sig_type=std_logic lab=Sb}
C {devices/lab_pin.sym} -880 290 2 1 {name=p162 sig_type=std_logic lab=S}
C {devices/lab_pin.sym} -880 270 2 1 {name=p163 sig_type=std_logic lab=Sb}
C {devices/lab_pin.sym} -700 290 2 1 {name=p164 sig_type=std_logic lab=S}
C {devices/lab_pin.sym} -700 270 2 1 {name=p165 sig_type=std_logic lab=Sb}
C {devices/lab_pin.sym} -520 290 2 1 {name=p166 sig_type=std_logic lab=S}
C {devices/lab_pin.sym} -520 270 2 1 {name=p167 sig_type=std_logic lab=Sb}
C {devices/lab_pin.sym} -340 290 2 1 {name=p168 sig_type=std_logic lab=S}
C {devices/lab_pin.sym} -340 270 2 1 {name=p169 sig_type=std_logic lab=Sb}
C {devices/lab_pin.sym} -160 290 2 1 {name=p170 sig_type=std_logic lab=S}
C {devices/lab_pin.sym} -160 270 2 1 {name=p171 sig_type=std_logic lab=Sb}
C {devices/lab_pin.sym} 20 290 2 1 {name=p172 sig_type=std_logic lab=S}
C {devices/lab_pin.sym} 20 270 2 1 {name=p173 sig_type=std_logic lab=Sb}
C {devices/lab_pin.sym} 380 -250 0 0 {name=p174 sig_type=std_logic lab=d11}
C {devices/lab_pin.sym} 380 -270 0 0 {name=p175 sig_type=std_logic lab=db11}
C {devices/lab_pin.sym} 560 -250 0 0 {name=p176 sig_type=std_logic lab=d10}
C {devices/lab_pin.sym} 560 -270 0 0 {name=p177 sig_type=std_logic lab=db10}
C {devices/lab_pin.sym} 740 -250 0 0 {name=p178 sig_type=std_logic lab=d9}
C {devices/lab_pin.sym} 740 -270 0 0 {name=p179 sig_type=std_logic lab=db9}
C {devices/lab_pin.sym} 380 290 0 0 {name=p180 sig_type=std_logic lab=db11}
C {devices/lab_pin.sym} 380 270 0 0 {name=p181 sig_type=std_logic lab=d11}
C {devices/lab_pin.sym} 560 290 0 0 {name=p182 sig_type=std_logic lab=db10}
C {devices/lab_pin.sym} 560 270 0 0 {name=p183 sig_type=std_logic lab=d10}
C {devices/lab_pin.sym} 740 290 0 0 {name=p184 sig_type=std_logic lab=db9}
C {devices/lab_pin.sym} 740 270 0 0 {name=p185 sig_type=std_logic lab=d9}
C {devices/lab_pin.sym} 920 -250 0 0 {name=p186 sig_type=std_logic lab=d8}
C {devices/lab_pin.sym} 920 270 0 0 {name=p187 sig_type=std_logic lab=d8}
C {devices/lab_pin.sym} 920 -270 0 0 {name=p188 sig_type=std_logic lab=db8}
C {devices/lab_pin.sym} 920 290 0 0 {name=p189 sig_type=std_logic lab=db8}
C {devices/lab_pin.sym} 1100 -250 0 0 {name=p190 sig_type=std_logic lab=d7}
C {devices/lab_pin.sym} 1100 270 0 0 {name=p191 sig_type=std_logic lab=d7}
C {devices/lab_pin.sym} 1100 -270 0 0 {name=p192 sig_type=std_logic lab=db7}
C {devices/lab_pin.sym} 1100 290 0 0 {name=p193 sig_type=std_logic lab=db7}
C {devices/lab_pin.sym} 1280 -250 2 0 {name=p194 sig_type=std_logic lab=d6}
C {devices/lab_pin.sym} 1280 270 2 0 {name=p195 sig_type=std_logic lab=d6}
C {devices/lab_pin.sym} 1280 -270 2 0 {name=p196 sig_type=std_logic lab=db6}
C {devices/lab_pin.sym} 1280 290 2 0 {name=p197 sig_type=std_logic lab=db6}
C {devices/lab_pin.sym} -750 -250 0 0 {name=p198 sig_type=std_logic lab=d5}
C {devices/lab_pin.sym} -750 270 0 0 {name=p199 sig_type=std_logic lab=d5}
C {devices/lab_pin.sym} -750 -270 0 0 {name=p200 sig_type=std_logic lab=db5}
C {devices/lab_pin.sym} -750 290 0 0 {name=p201 sig_type=std_logic lab=db5}
C {devices/lab_pin.sym} -570 -250 0 0 {name=p202 sig_type=std_logic lab=d4}
C {devices/lab_pin.sym} -570 -270 0 0 {name=p203 sig_type=std_logic lab=db4}
C {devices/lab_pin.sym} -570 290 0 0 {name=p204 sig_type=std_logic lab=db4}
C {devices/lab_pin.sym} -570 270 0 0 {name=p205 sig_type=std_logic lab=d4}
C {devices/lab_pin.sym} -390 270 0 0 {name=p206 sig_type=std_logic lab=d3}
C {devices/lab_pin.sym} -390 290 0 0 {name=p207 sig_type=std_logic lab=db3}
C {devices/lab_pin.sym} -390 -270 0 0 {name=p208 sig_type=std_logic lab=db3}
C {devices/lab_pin.sym} -390 -250 0 0 {name=p209 sig_type=std_logic lab=d3}
C {devices/lab_pin.sym} -210 -250 0 0 {name=p210 sig_type=std_logic lab=d2}
C {devices/lab_pin.sym} -210 -270 0 0 {name=p211 sig_type=std_logic lab=db2}
C {devices/lab_pin.sym} -210 290 0 0 {name=p212 sig_type=std_logic lab=db2}
C {devices/lab_pin.sym} -210 270 0 0 {name=p213 sig_type=std_logic lab=d2}
C {devices/lab_pin.sym} -30 270 0 0 {name=p214 sig_type=std_logic lab=d1}
C {devices/lab_pin.sym} -30 290 0 0 {name=p215 sig_type=std_logic lab=db1}
C {devices/lab_pin.sym} -30 -270 0 0 {name=p216 sig_type=std_logic lab=db1}
C {devices/lab_pin.sym} -30 -250 0 0 {name=p217 sig_type=std_logic lab=d1}
C {devices/lab_pin.sym} 150 -250 0 0 {name=p218 sig_type=std_logic lab=d0}
C {devices/lab_pin.sym} 150 270 0 0 {name=p219 sig_type=std_logic lab=d0}
C {devices/lab_pin.sym} 150 -270 0 0 {name=p220 sig_type=std_logic lab=db0}
C {devices/lab_pin.sym} 150 290 0 0 {name=p221 sig_type=std_logic lab=db0}
C {devices/ipin.sym} -1510 -430 0 0 {name=p227 lab=Vin_n}
C {devices/ipin.sym} -1540 410 0 0 {name=p228 lab=Vin_p}
C {devices/lab_pin.sym} -1510 -370 0 0 {name=p229 sig_type=std_logic lab=S}
C {devices/lab_pin.sym} -1510 -400 0 0 {name=p230 sig_type=std_logic lab=Sb}
C {devices/lab_pin.sym} -1540 470 0 0 {name=p231 sig_type=std_logic lab=S}
C {devices/lab_pin.sym} -1540 440 0 0 {name=p232 sig_type=std_logic lab=Sb}
C {devices/lab_pin.sym} -1220 -400 3 0 {name=p233 sig_type=std_logic lab=in_n_sampled}
C {devices/lab_pin.sym} -1240 440 1 0 {name=p234 sig_type=std_logic lab=in_p_sampled}
C {transmission_gate.sym} 1630 20 1 0 {name=x27
}
C {devices/lab_pin.sym} 1690 -30 2 0 {name=p42 sig_type=std_logic lab=VDD
}
C {devices/lab_pin.sym} 1570 -30 0 0 {name=p70 sig_type=std_logic lab=VSS
}
C {devices/lab_pin.sym} 1660 10 2 0 {name=p71 sig_type=std_logic lab=S
}
C {devices/lab_pin.sym} 1580 10 0 0 {name=p224 sig_type=std_logic lab=Sb
}
C {Inverter.sym} -450 -640 0 0 {name=x2}
C {Inverter.sym} -310 -640 0 0 {name=x3}
C {Inverter.sym} -130 -640 0 0 {name=x4}
C {Inverter.sym} 10 -640 0 0 {name=x5}
C {Inverter.sym} 190 -640 0 0 {name=x6}
C {Inverter.sym} 330 -640 0 0 {name=x7}
C {Inverter.sym} 520 -640 0 0 {name=x8}
C {Inverter.sym} 660 -640 0 0 {name=x9}
C {Inverter.sym} 540 -770 2 0 {name=x10}
C {Inverter.sym} 400 -770 2 0 {name=x11}
C {Inverter.sym} 220 -770 2 0 {name=x12}
C {Inverter.sym} 80 -770 2 0 {name=x13}
C {Inverter.sym} -100 -770 2 0 {name=x14}
C {Inverter.sym} -240 -770 2 0 {name=x15}
C {Inverter.sym} -430 -770 2 0 {name=x16}
C {Inverter.sym} -570 -770 2 0 {name=x17}
C {Inverter.sym} -450 -890 0 0 {name=x18}
C {Inverter.sym} -310 -890 0 0 {name=x19}
C {Inverter.sym} -130 -890 0 0 {name=x20}
C {Inverter.sym} 10 -890 0 0 {name=x21}
C {Inverter.sym} 190 -890 0 0 {name=x22}
C {Inverter.sym} 330 -890 0 0 {name=x23}
C {Inverter.sym} 520 -890 0 0 {name=x24}
C {Inverter.sym} 660 -890 0 0 {name=x25}
C {devices/lab_pin.sym} -510 -710 0 0 {name=p238 sig_type=std_logic lab=VDD}
C {devices/lab_pin.sym} -510 -950 0 0 {name=p239 sig_type=std_logic lab=VDD}
C {devices/lab_pin.sym} -420 -640 1 0 {name=p240 sig_type=std_logic lab=db0}
C {devices/lab_pin.sym} -280 -640 1 0 {name=p241 sig_type=std_logic lab=d0}
C {devices/lab_pin.sym} 50 -640 1 0 {name=p242 sig_type=std_logic lab=d1}
C {devices/lab_pin.sym} -100 -640 1 0 {name=p243 sig_type=std_logic lab=db1}
C {devices/lab_pin.sym} 370 -640 1 0 {name=p244 sig_type=std_logic lab=d2}
C {devices/lab_pin.sym} 220 -640 1 0 {name=p245 sig_type=std_logic lab=db2}
C {devices/lab_pin.sym} 550 -640 1 0 {name=p246 sig_type=std_logic lab=db3}
C {devices/lab_pin.sym} 700 -640 2 0 {name=p247 sig_type=std_logic lab=d3}
C {devices/lab_pin.sym} 370 -770 3 0 {name=p248 sig_type=std_logic lab=d4}
C {devices/lab_pin.sym} 510 -770 3 0 {name=p249 sig_type=std_logic lab=db4}
C {devices/lab_pin.sym} 50 -770 3 0 {name=p250 sig_type=std_logic lab=d5}
C {devices/lab_pin.sym} 190 -770 3 0 {name=p251 sig_type=std_logic lab=db5}
C {devices/lab_pin.sym} -270 -770 3 0 {name=p252 sig_type=std_logic lab=d6}
C {devices/lab_pin.sym} -130 -770 3 0 {name=p253 sig_type=std_logic lab=db6}
C {devices/lab_pin.sym} -600 -770 3 0 {name=p254 sig_type=std_logic lab=d7}
C {devices/lab_pin.sym} -460 -770 3 0 {name=p255 sig_type=std_logic lab=db7}
C {devices/lab_pin.sym} -280 -890 3 0 {name=p256 sig_type=std_logic lab=d8}
C {devices/lab_pin.sym} -420 -890 3 0 {name=p257 sig_type=std_logic lab=db8}
C {devices/lab_pin.sym} 40 -890 3 0 {name=p258 sig_type=std_logic lab=d9}
C {devices/lab_pin.sym} -100 -890 3 0 {name=p259 sig_type=std_logic lab=db9}
C {devices/lab_pin.sym} 220 -890 3 0 {name=p260 sig_type=std_logic lab=db10}
C {devices/lab_pin.sym} 360 -890 3 0 {name=p261 sig_type=std_logic lab=d10}
C {devices/lab_pin.sym} 550 -890 3 0 {name=p262 sig_type=std_logic lab=db11}
C {devices/lab_pin.sym} 690 -890 3 0 {name=p263 sig_type=std_logic lab=d11}
C {devices/lab_pin.sym} -580 -640 0 0 {name=p264 sig_type=std_logic lab=di0}
C {devices/lab_pin.sym} -240 -640 1 0 {name=p265 sig_type=std_logic lab=di1}
C {devices/lab_pin.sym} 80 -640 1 0 {name=p266 sig_type=std_logic lab=di2}
C {devices/lab_pin.sym} 400 -640 1 0 {name=p267 sig_type=std_logic lab=di3}
C {devices/lab_pin.sym} 660 -770 1 0 {name=p268 sig_type=std_logic lab=di4}
C {devices/lab_pin.sym} 340 -770 1 0 {name=p269 sig_type=std_logic lab=di5}
C {devices/lab_pin.sym} 10 -770 1 0 {name=p270 sig_type=std_logic lab=di6}
C {devices/lab_pin.sym} -310 -770 1 0 {name=p271 sig_type=std_logic lab=di7}
C {devices/lab_pin.sym} -570 -890 1 0 {name=p272 sig_type=std_logic lab=di8}
C {devices/lab_pin.sym} -240 -890 1 0 {name=p273 sig_type=std_logic lab=di9}
C {devices/lab_pin.sym} 80 -890 1 0 {name=p274 sig_type=std_logic lab=di10}
C {devices/lab_pin.sym} 410 -890 1 0 {name=p275 sig_type=std_logic lab=di11}
C {devices/lab_pin.sym} -510 -580 0 0 {name=p276 sig_type=std_logic lab=VSS}
C {devices/lab_pin.sym} -510 -840 0 0 {name=p277 sig_type=std_logic lab=VSS}
C {transmission_gate.sym} 1830 -120 1 0 {name=x28}
C {transmission_gate.sym} 1830 150 3 0 {name=x29}
C {devices/lab_pin.sym} 1740 200 0 0 {name=p41 sig_type=std_logic lab=VDD}
C {devices/lab_pin.sym} 1920 -170 2 0 {name=p43 sig_type=std_logic lab=VDD}
C {devices/lab_pin.sym} 1740 -170 0 0 {name=p72 sig_type=std_logic lab=VSS
}
C {devices/lab_pin.sym} 1920 200 2 0 {name=p73 sig_type=std_logic lab=VSS}
C {devices/lab_pin.sym} 1830 -220 2 0 {name=p74 sig_type=std_logic lab=Vcm}
C {devices/lab_pin.sym} 1830 260 2 0 {name=p75 sig_type=std_logic lab=Vcm}
C {devices/lab_pin.sym} 1890 -130 2 0 {name=p222 sig_type=std_logic lab=S}
C {devices/lab_pin.sym} 1760 160 0 0 {name=p223 sig_type=std_logic lab=S}
C {devices/lab_pin.sym} 1750 -130 0 0 {name=p225 sig_type=std_logic lab=Sb
}
C {devices/lab_pin.sym} 1910 160 2 0 {name=p226 sig_type=std_logic lab=Sb}
C {Network_Switch.sym} 1410 -270 0 0 {name=x56
}
C {devices/lab_pin.sym} 1350 -300 0 0 {name=p99 sig_type=std_logic lab=VDD
}
C {devices/lab_pin.sym} 1350 -240 0 0 {name=p101 sig_type=std_logic lab=VSS
}
C {devices/lab_pin.sym} 1350 -280 2 1 {name=p103 sig_type=std_logic lab=S
}
C {devices/lab_pin.sym} 1350 -260 2 1 {name=p105 sig_type=std_logic lab=Sb
}
C {devices/lab_pin.sym} 1470 -280 2 0 {name=p107 sig_type=std_logic lab=VDD
}
C {devices/lab_pin.sym} 1470 -260 2 0 {name=p109 sig_type=std_logic lab=VSS
}
C {Network_Switch.sym} 1410 280 2 1 {name=x57
}
C {devices/lab_pin.sym} 1350 310 2 1 {name=p111 sig_type=std_logic lab=VDD
}
C {devices/lab_pin.sym} 1350 250 2 1 {name=p113 sig_type=std_logic lab=VSS
}
C {devices/lab_pin.sym} 1350 290 0 0 {name=p115 sig_type=std_logic lab=S
}
C {devices/lab_pin.sym} 1350 270 0 0 {name=p117 sig_type=std_logic lab=Sb
}
C {devices/lab_pin.sym} 1470 290 0 1 {name=p119 sig_type=std_logic lab=VDD
}
C {devices/lab_pin.sym} 1470 270 0 1 {name=p121 sig_type=std_logic lab=VSS
}
C {sky130_fd_pr/cap_mim_m3_1.sym} 1060 -120 0 0 {name=C16 model=cap_mim_m3_1 W=1.198 L=1.198 MF=2 spiceprefix=X}
C {sky130_fd_pr/cap_mim_m3_1.sym} 880 -120 0 0 {name=C17 model=cap_mim_m3_1 W=1.763 L=1.763 MF=2 spiceprefix=X}
C {sky130_fd_pr/cap_mim_m3_1.sym} 700 -120 0 0 {name=C18 model=cap_mim_m3_1 W=2.57 L=2.57 MF=2 spiceprefix=X}
C {sky130_fd_pr/cap_mim_m3_1.sym} 520 -120 0 0 {name=C19 model=cap_mim_m3_1 W=3.705 L=3.705 MF=2 spiceprefix=X}
C {sky130_fd_pr/cap_mim_m3_1.sym} 340 -120 0 0 {name=C20 model=cap_mim_m3_1 W=5.31 L=5.31 MF=2 spiceprefix=X}
C {sky130_fd_pr/cap_mim_m3_1.sym} 1790 -700 0 0 {name=C2 model=cap_mim_m3_1 W=1 L=1 MF=1 spiceprefix=X
spice_ignore=true}
C {sky130_fd_pr/cap_mim_m3_1.sym} 1610 -700 0 0 {name=C3 model=cap_mim_m3_1 W=1.485 L=1.48 MF=1 spiceprefix=X
spice_ignore=true}
C {sky130_fd_pr/cap_mim_m3_1.sym} 1430 -700 0 0 {name=C4 model=cap_mim_m3_1 W=2.17 L=2.17 MF=1 spiceprefix=X
spice_ignore=true}
C {sky130_fd_pr/cap_mim_m3_1.sym} 1250 -700 0 0 {name=C5 model=cap_mim_m3_1 W=3.14 L=3.14 MF=1 spiceprefix=X
spice_ignore=true}
C {sky130_fd_pr/cap_mim_m3_1.sym} 1070 -700 0 0 {name=C6 model=cap_mim_m3_1 W=4.515 L=4.515 MF=1 spiceprefix=X
spice_ignore=true}
C {sky130_fd_pr/cap_mim_m3_1.sym} 890 -700 0 0 {name=C7 model=cap_mim_m3_1 W=6.46 L=6.46 MF=1 spiceprefix=X
spice_ignore=true}
C {sky130_fd_pr/cap_mim_m3_1.sym} 1760 -880 0 0 {name=C9 model=cap_mim_m3_1 W=2.1 L=2.1 MF=6 spiceprefix=X
spice_ignore=true}
C {sky130_fd_pr/cap_mim_m3_1.sym} 1580 -880 0 0 {name=C10 model=cap_mim_m3_1 W=3.045 L=3.045 MF=6 spiceprefix=X
spice_ignore=true}
C {sky130_fd_pr/cap_mim_m3_1.sym} 1400 -880 0 0 {name=C11 model=cap_mim_m3_1 W=4.38 L=4.38 MF=6 spiceprefix=X
spice_ignore=true}
C {sky130_fd_pr/cap_mim_m3_1.sym} 1220 -880 0 0 {name=C12 model=cap_mim_m3_1 W=6.27 L=6.27 MF=6 spiceprefix=X
spice_ignore=true}
C {sky130_fd_pr/cap_mim_m3_1.sym} 1040 -880 0 0 {name=C13 model=cap_mim_m3_1 W=8.95 L=8.95 MF=6 spiceprefix=X
spice_ignore=true}
C {sky130_fd_pr/cap_mim_m3_1.sym} 860 -880 0 0 {name=C14 model=cap_mim_m3_1 W=12.75 L=12.75 MF=6 spiceprefix=X
spice_ignore=true}
C {sky130_fd_pr/cap_mim_m3_1.sym} 1300 690 0 0 {name=C22 model=cap_mim_m3_1 W=2.1 L=2.1 MF=4 spiceprefix=X
spice_ignore=true}
C {sky130_fd_pr/cap_mim_m3_1.sym} 1120 690 0 0 {name=C23 model=cap_mim_m3_1 W=3.045 L=3.045 MF=4 spiceprefix=X
spice_ignore=true}
C {sky130_fd_pr/cap_mim_m3_1.sym} 940 690 0 0 {name=C24 model=cap_mim_m3_1 W=4.38 L=4.38 MF=4 spiceprefix=X
spice_ignore=true}
C {sky130_fd_pr/cap_mim_m3_1.sym} 760 690 0 0 {name=C25 model=cap_mim_m3_1 W=6.27 L=6.27 MF=4 spiceprefix=X
spice_ignore=true}
C {sky130_fd_pr/cap_mim_m3_1.sym} 580 690 0 0 {name=C26 model=cap_mim_m3_1 W=8.94 L=8.94 MF=4 spiceprefix=X
spice_ignore=true}
C {sky130_fd_pr/cap_mim_m3_1.sym} 400 690 0 0 {name=C27 model=cap_mim_m3_1 W=12.73 L=12.73 MF=4 spiceprefix=X
spice_ignore=true}
C {bootstrapped_switch_SH.sym} -1360 -390 0 0 {name=x1}
C {bootstrapped_switch_SH.sym} -1390 450 0 0 {name=x26}
C {transmission_gate.sym} -1190 20 1 0 {name=x58
}
C {devices/lab_pin.sym} -1100 -30 2 0 {name=p20 sig_type=std_logic lab=VDD
}
C {devices/lab_pin.sym} -1280 -30 0 0 {name=p28 sig_type=std_logic lab=VSS
}
C {devices/lab_pin.sym} -1120 10 2 0 {name=p83 sig_type=std_logic lab=S
}
C {devices/lab_pin.sym} -1270 10 0 0 {name=p85 sig_type=std_logic lab=Sb
}
C {transmission_gate.sym} -1340 -120 1 0 {name=x59}
C {transmission_gate.sym} -1340 150 3 0 {name=x60}
C {devices/lab_pin.sym} -1430 200 0 0 {name=p87 sig_type=std_logic lab=VDD}
C {devices/lab_pin.sym} -1250 -170 2 0 {name=p89 sig_type=std_logic lab=VDD}
C {devices/lab_pin.sym} -1430 -170 0 0 {name=p91 sig_type=std_logic lab=VSS}
C {devices/lab_pin.sym} -1250 200 2 0 {name=p93 sig_type=std_logic lab=VSS}
C {devices/lab_pin.sym} -1340 -220 2 0 {name=p95 sig_type=std_logic lab=Vcm}
C {devices/lab_pin.sym} -1340 260 2 0 {name=p97 sig_type=std_logic lab=Vcm}
C {devices/lab_pin.sym} -1280 -130 2 0 {name=p123 sig_type=std_logic lab=S}
C {devices/lab_pin.sym} -1410 160 0 0 {name=p125 sig_type=std_logic lab=S}
C {devices/lab_pin.sym} -1420 -130 0 0 {name=p235 sig_type=std_logic lab=Sb}
C {devices/lab_pin.sym} -1260 160 2 0 {name=p236 sig_type=std_logic lab=Sb}
C {devices/lab_pin.sym} -1340 -50 0 0 {name=p237 sig_type=std_logic lab=node_n}
C {devices/lab_pin.sym} -1340 70 0 0 {name=p278 sig_type=std_logic lab=node_p}
C {sky130_fd_pr/cap_mim_m3_1.sym} 1430 -120 0 0 {name=C43 model=cap_mim_m3_1 W=0.8 L=0.8 MF=2 spiceprefix=X}
C {sky130_fd_pr/cap_mim_m3_1.sym} 1240 -120 0 0 {name=C21 model=cap_mim_m3_1 W=0.8 L=0.8 MF=2 spiceprefix=X}
C {sky130_fd_pr/cap_mim_m3_1.sym} 1750 -1010 0 0 {name=C44 model=cap_mim_m3_1 W=0.7 L=0.7 MF=4 spiceprefix=X
spice_ignore=true}
C {sky130_fd_pr/cap_mim_m3_1.sym} 1570 -1010 0 0 {name=C47 model=cap_mim_m3_1 W=1.055 L=1.055 MF=4 spiceprefix=X
spice_ignore=true}
C {sky130_fd_pr/cap_mim_m3_1.sym} 1390 -1010 0 0 {name=C48 model=cap_mim_m3_1 W=1.56 L=1.56 MF=4 spiceprefix=X
spice_ignore=true}
C {sky130_fd_pr/cap_mim_m3_1.sym} 1210 -1010 0 0 {name=C49 model=cap_mim_m3_1 W=2.278 L=2.278 MF=4 spiceprefix=X
spice_ignore=true}
C {sky130_fd_pr/cap_mim_m3_1.sym} 1030 -1010 0 0 {name=C50 model=cap_mim_m3_1 W=3.295 L=3.295 MF=4 spiceprefix=X
spice_ignore=true}
C {sky130_fd_pr/cap_mim_m3_1.sym} 850 -1010 0 0 {name=C51 model=cap_mim_m3_1 W=4.733 L=4.733 MF=4 spiceprefix=X
spice_ignore=true}
C {sky130_fd_pr/cap_mim_m3_1.sym} 1060 140 0 0 {name=C37 model=cap_mim_m3_1 W=1.198 L=1.198 MF=2 spiceprefix=X}
C {sky130_fd_pr/cap_mim_m3_1.sym} 880 140 0 0 {name=C38 model=cap_mim_m3_1 W=1.763 L=1.763 MF=2 spiceprefix=X}
C {sky130_fd_pr/cap_mim_m3_1.sym} 700 140 0 0 {name=C39 model=cap_mim_m3_1 W=2.57 L=2.57 MF=2 spiceprefix=X}
C {sky130_fd_pr/cap_mim_m3_1.sym} 520 140 0 0 {name=C40 model=cap_mim_m3_1 W=3.705 L=3.705 MF=2 spiceprefix=X}
C {sky130_fd_pr/cap_mim_m3_1.sym} 340 140 0 0 {name=C41 model=cap_mim_m3_1 W=5.31 L=5.31 MF=2 spiceprefix=X}
C {sky130_fd_pr/cap_mim_m3_1.sym} 1430 140 0 0 {name=C42 model=cap_mim_m3_1 W=0.8 L=0.8 MF=2 spiceprefix=X}
C {sky130_fd_pr/cap_mim_m3_1.sym} 1240 140 0 0 {name=C52 model=cap_mim_m3_1 W=0.8 L=0.8 MF=2 spiceprefix=X}
C {sky130_fd_pr/cap_mim_m3_1.sym} -70 -120 0 0 {name=C1 model=cap_mim_m3_1 W=1.198 L=1.198 MF=2 spiceprefix=X}
C {sky130_fd_pr/cap_mim_m3_1.sym} -250 -120 0 0 {name=C8 model=cap_mim_m3_1 W=1.763 L=1.763 MF=2 spiceprefix=X}
C {sky130_fd_pr/cap_mim_m3_1.sym} -430 -120 0 0 {name=C15 model=cap_mim_m3_1 W=2.57 L=2.57 MF=2 spiceprefix=X}
C {sky130_fd_pr/cap_mim_m3_1.sym} -610 -120 0 0 {name=C28 model=cap_mim_m3_1 W=3.705 L=3.705 MF=2 spiceprefix=X}
C {sky130_fd_pr/cap_mim_m3_1.sym} -790 -120 0 0 {name=C29 model=cap_mim_m3_1 W=5.31 L=5.31 MF=2 spiceprefix=X}
C {sky130_fd_pr/cap_mim_m3_1.sym} 110 -120 0 0 {name=C30 model=cap_mim_m3_1 W=0.8 L=0.8 MF=2 spiceprefix=X}
C {sky130_fd_pr/cap_mim_m3_1.sym} -70 140 0 0 {name=C31 model=cap_mim_m3_1 W=1.198 L=1.198 MF=2 spiceprefix=X}
C {sky130_fd_pr/cap_mim_m3_1.sym} -250 140 0 0 {name=C32 model=cap_mim_m3_1 W=1.763 L=1.763 MF=2 spiceprefix=X}
C {sky130_fd_pr/cap_mim_m3_1.sym} -430 140 0 0 {name=C33 model=cap_mim_m3_1 W=2.57 L=2.57 MF=2 spiceprefix=X}
C {sky130_fd_pr/cap_mim_m3_1.sym} -610 140 0 0 {name=C34 model=cap_mim_m3_1 W=3.705 L=3.705 MF=2 spiceprefix=X}
C {sky130_fd_pr/cap_mim_m3_1.sym} -790 140 0 0 {name=C35 model=cap_mim_m3_1 W=5.31 L=5.31 MF=2 spiceprefix=X}
C {sky130_fd_pr/cap_mim_m3_1.sym} 110 140 0 0 {name=C36 model=cap_mim_m3_1 W=0.8 L=0.8 MF=2 spiceprefix=X}
C {sky130_fd_pr/cap_mim_m3_1.sym} 230 -50 3 0 {name=C45 model=cap_mim_m3_1 W=0.8 L=0.8 MF=2 spiceprefix=X}
C {sky130_fd_pr/cap_mim_m3_1.sym} 230 70 3 0 {name=C46 model=cap_mim_m3_1 W=0.8 L=0.8 MF=2 spiceprefix=X}
